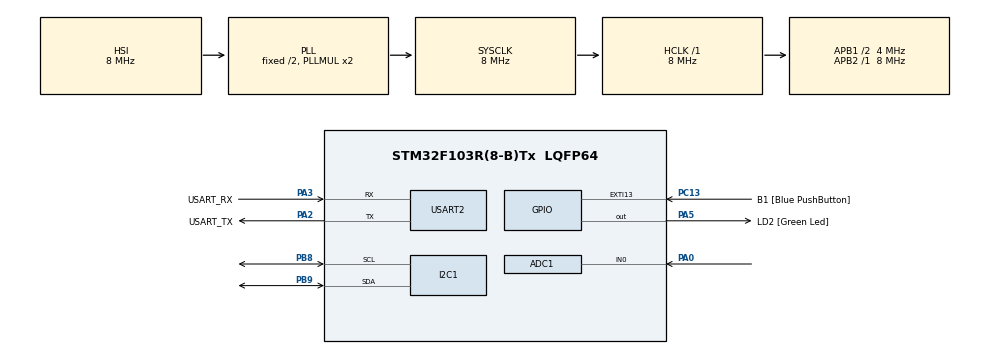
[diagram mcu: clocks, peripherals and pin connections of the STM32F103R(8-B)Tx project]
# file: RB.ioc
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ADC1.Channel-0\#ChannelRegularConversion=ADC_CHANNEL_0
ADC1.ContinuousConvMode=ENABLE
ADC1.NbrOfConversionFlag=1
ADC1.Rank-0\#ChannelRegularConversion=1
ADC1.SamplingTime-0\#ChannelRegularConversion=ADC_SAMPLETIME_1CYCLE_5
ADC1.master=1
Mcu.Family=STM32F1
Mcu.Name=STM32F103R(8-B)Tx
Mcu.Package=LQFP64
NVIC.ADC1_2_IRQn=true\:0\:0\:false\:false\:true\:true\:true\:true
NVIC.EXTI15_10_IRQn=true\:0\:0\:false\:false\:true\:true\:true\:true
NVIC.PriorityGroup=NVIC_PRIORITYGROUP_4
NVIC.TIM2_IRQn=true\:0\:0\:false\:false\:true\:true\:true\:true
PA0-WKUP.Signal=ADCx_IN0
PA13.GPIO_Label=TMS
PA13.Mode=Serial_Wire
PA13.Signal=SYS_JTMS-SWDIO
PA14.GPIO_Label=TCK
PA14.Mode=Serial_Wire
PA14.Signal=SYS_JTCK-SWCLK
PA2.GPIO_Label=USART_TX
PA2.GPIO_Mode=GPIO_MODE_AF_PP
PA2.GPIO_PuPd=GPIO_NOPULL
PA2.GPIO_Speed=GPIO_SPEED_FREQ_LOW
PA2.Mode=Asynchronous
PA2.Signal=USART2_TX
PA3.GPIO_Label=USART_RX
PA3.GPIO_Mode=GPIO_MODE_AF_PP
PA3.GPIO_PuPd=GPIO_NOPULL
PA3.GPIO_Speed=GPIO_SPEED_FREQ_LOW
PA3.Mode=Asynchronous
PA3.Signal=USART2_RX
PA5.GPIO_Label=LD2 [Green Led]
PA5.GPIO_ModeDefaultOutputPP=GPIO_MODE_OUTPUT_PP
PA5.GPIO_PuPd=GPIO_NOPULL
PA5.GPIO_Speed=GPIO_SPEED_FREQ_LOW
PA5.Signal=GPIO_Output
PB3.GPIO_Label=SWO
PB3.Signal=SYS_JTDO-TRACESWO
PB8.Mode=I2C
PB8.Signal=I2C1_SCL
PB9.Mode=I2C
PB9.Signal=I2C1_SDA
PC13-TAMPER-RTC.GPIO_Label=B1 [Blue PushButton]
PC13-TAMPER-RTC.GPIO_PuPd=GPIO_NOPULL
PC13-TAMPER-RTC.Signal=GPXTI13
PC14-OSC32_IN.Mode=LSE-External-Oscillator
PC14-OSC32_IN.Signal=RCC_OSC32_IN
PC15-OSC32_OUT.Mode=LSE-External-Oscillator
PC15-OSC32_OUT.Signal=RCC_OSC32_OUT
PD0-OSC_IN.Mode=HSE-External-Clock-Source
PD0-OSC_IN.Signal=RCC_OSC_IN
PD1-OSC_OUT.Mode=HSE-External-Clock-Source
PD1-OSC_OUT.Signal=RCC_OSC_OUT
ProjectManager.HeapSize=0x200
ProjectManager.StackSize=0x400
ProjectManager.TargetToolchain=STM32CubeIDE
RCC.AHBFreq_Value=8000000
RCC.APB1CLKDivider=RCC_HCLK_DIV2
RCC.APB1Freq_Value=4000000
RCC.APB1TimFreq_Value=8000000
RCC.APB2Freq_Value=8000000
RCC.APB2TimFreq_Value=8000000
RCC.HCLKFreq_Value=8000000
RCC.RTCClockSelection=RCC_RTCCLKSOURCE_LSE
RCC.SYSCLKFreq_VALUE=8000000
RCC.SYSCLKSource=RCC_SYSCLKSOURCE_PLLCLK
RCC.USBFreq_Value=8000000
SH.ADCx_IN0.0=ADC1_IN0,IN0
TIM2.Period=9
TIM2.Prescaler=63999
USART2.VirtualMode=VM_ASYNC
VP_TIM2_VS_ClockSourceINT.Mode=Internal
board=NUCLEO-F103RB

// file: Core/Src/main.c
/* USER CODE BEGIN Header */
/**
  ******************************************************************************
  * @file           : main.c
  * @brief          : Main program body
  ******************************************************************************
  * @attention
  *
  * Copyright (c) 2024 STMicroelectronics.
  * All rights reserved.
  *
  * This software is licensed under terms that can be found in the LICENSE file
  * in the root directory of this software component.
  * If no LICENSE file comes with this software, it is provided AS-IS.
  *
  ******************************************************************************
  */
/* USER CODE END Header */
#include "main.h"

/* USER CODE BEGIN Includes */
#include "i2c-lcd.h"
#include "input_processing.h"
#include "input_reading.h"
#include "scheduler.h"
#include "led_display.h"
/* USER CODE END Includes */

/* USER CODE BEGIN PD */
TIM_HandleTypeDef htim2;

/* USER CODE END PD */

ADC_HandleTypeDef hadc1;

I2C_HandleTypeDef hi2c1;

TIM_HandleTypeDef htim2;

UART_HandleTypeDef huart2;

void SystemClock_Config(void);
static void MX_GPIO_Init(void);
static void MX_USART2_UART_Init(void);
static void MX_I2C1_Init(void);
static void MX_ADC1_Init(void);
static void MX_TIM2_Init(void);
/* USER CODE BEGIN PFP */
ADC_HandleTypeDef hadc1;
/* USER CODE END PFP */

/* USER CODE BEGIN 0 */
void HAL_ADC_ConvCpltCallback(ADC_HandleTypeDef * hadc){

}
void HAL_TIM_PeriodElapsedCallback (TIM_HandleTypeDef *htim)
{
	  SCH_Update();  // Cập nhật scheduler mỗi 1ms

	}
/* USER CODE END 0 */

int main(void)
{

  /* MCU Configuration--------------------------------------------------------*/

  /* Reset of all peripherals, Initializes the Flash interface and the Systick. */
  HAL_Init();

  /* Configure the system clock */
  SystemClock_Config();

  /* Initialize all configured peripherals */
  MX_GPIO_Init();
  MX_USART2_UART_Init();
  MX_I2C1_Init();
  MX_ADC1_Init();
  MX_TIM2_Init();
  /* USER CODE BEGIN 2 */
  lcd_init();
  //lcd_clear();
  HAL_TIM_Base_Start_IT(&htim2);
  SCH_Init();
  //HAL_ADC_Start_IT(&hadc1);
  /* USER CODE END 2 */

  /* Infinite loop */
  /* USER CODE BEGIN WHILE */
  SCH_Add_Task(timeledlight, 0, 1);
  SCH_Add_Task(button_reading, 1, 1);
  SCH_Add_Task(handle_mode, 3, 10);
  SCH_Add_Task(fsm_for_input_processing, 4, 1);
//  SCH_Add_Task(timeledlight, 500, 500);
  while (1)
  {
	  SCH_Dispatch_Tasks();
	  lcd_goto_XY(1, 0);
	  //lcd_send_string("hehe");
    /* USER CODE END WHILE */

  }
}

void SystemClock_Config(void)
{
  RCC_OscInitTypeDef RCC_OscInitStruct = {0};
  RCC_ClkInitTypeDef RCC_ClkInitStruct = {0};
  RCC_PeriphCLKInitTypeDef PeriphClkInit = {0};

  /** Initializes the RCC Oscillators according to the specified parameters
  * in the RCC_OscInitTypeDef structure.
  */
  RCC_OscInitStruct.OscillatorType = RCC_OSCILLATORTYPE_HSI;
  RCC_OscInitStruct.HSIState = RCC_HSI_ON;
  RCC_OscInitStruct.HSICalibrationValue = RCC_HSICALIBRATION_DEFAULT;
  RCC_OscInitStruct.PLL.PLLState = RCC_PLL_ON;
  RCC_OscInitStruct.PLL.PLLSource = RCC_PLLSOURCE_HSI_DIV2;
  RCC_OscInitStruct.PLL.PLLMUL = RCC_PLL_MUL2;
  if (HAL_RCC_OscConfig(&RCC_OscInitStruct) != HAL_OK)
  {
    Error_Handler();
  }

  /** Initializes the CPU, AHB and APB buses clocks
  */
  RCC_ClkInitStruct.ClockType = RCC_CLOCKTYPE_HCLK|RCC_CLOCKTYPE_SYSCLK
                              |RCC_CLOCKTYPE_PCLK1|RCC_CLOCKTYPE_PCLK2;
  RCC_ClkInitStruct.SYSCLKSource = RCC_SYSCLKSOURCE_PLLCLK;
  RCC_ClkInitStruct.AHBCLKDivider = RCC_SYSCLK_DIV1;
  RCC_ClkInitStruct.APB1CLKDivider = RCC_HCLK_DIV2;
  RCC_ClkInitStruct.APB2CLKDivider = RCC_HCLK_DIV1;

  if (HAL_RCC_ClockConfig(&RCC_ClkInitStruct, FLASH_LATENCY_0) != HAL_OK)
  {
    Error_Handler();
  }
  PeriphClkInit.PeriphClockSelection = RCC_PERIPHCLK_ADC;
  PeriphClkInit.AdcClockSelection = RCC_ADCPCLK2_DIV2;
  if (HAL_RCCEx_PeriphCLKConfig(&PeriphClkInit) != HAL_OK)
  {
    Error_Handler();
  }
}

static void MX_ADC1_Init(void)
{

  ADC_ChannelConfTypeDef sConfig = {0};

  /** Common config
  */
  hadc1.Instance = ADC1;
  hadc1.Init.ScanConvMode = ADC_SCAN_DISABLE;
  hadc1.Init.ContinuousConvMode = ENABLE;
  hadc1.Init.DiscontinuousConvMode = DISABLE;
  hadc1.Init.ExternalTrigConv = ADC_SOFTWARE_START;
  hadc1.Init.DataAlign = ADC_DATAALIGN_RIGHT;
  hadc1.Init.NbrOfConversion = 1;
  if (HAL_ADC_Init(&hadc1) != HAL_OK)
  {
    Error_Handler();
  }

  /** Configure Regular Channel
  */
  sConfig.Channel = ADC_CHANNEL_0;
  sConfig.Rank = ADC_REGULAR_RANK_1;
  sConfig.SamplingTime = ADC_SAMPLETIME_1CYCLE_5;
  if (HAL_ADC_ConfigChannel(&hadc1, &sConfig) != HAL_OK)
  {
    Error_Handler();
  }

}

static void MX_I2C1_Init(void)
{

  hi2c1.Instance = I2C1;
  hi2c1.Init.ClockSpeed = 100000;
  hi2c1.Init.DutyCycle = I2C_DUTYCYCLE_2;
  hi2c1.Init.OwnAddress1 = 0;
  hi2c1.Init.AddressingMode = I2C_ADDRESSINGMODE_7BIT;
  hi2c1.Init.DualAddressMode = I2C_DUALADDRESS_DISABLE;
  hi2c1.Init.OwnAddress2 = 0;
  hi2c1.Init.GeneralCallMode = I2C_GENERALCALL_DISABLE;
  hi2c1.Init.NoStretchMode = I2C_NOSTRETCH_DISABLE;
  if (HAL_I2C_Init(&hi2c1) != HAL_OK)
  {
    Error_Handler();
  }

}

static void MX_TIM2_Init(void)
{

  TIM_ClockConfigTypeDef sClockSourceConfig = {0};
  TIM_MasterConfigTypeDef sMasterConfig = {0};

  htim2.Instance = TIM2;
  htim2.Init.Prescaler = 63999;
  htim2.Init.CounterMode = TIM_COUNTERMODE_UP;
  htim2.Init.Period = 9;
  htim2.Init.ClockDivision = TIM_CLOCKDIVISION_DIV1;
  htim2.Init.AutoReloadPreload = TIM_AUTORELOAD_PRELOAD_DISABLE;
  if (HAL_TIM_Base_Init(&htim2) != HAL_OK)
  {
    Error_Handler();
  }
  sClockSourceConfig.ClockSource = TIM_CLOCKSOURCE_INTERNAL;
  if (HAL_TIM_ConfigClockSource(&htim2, &sClockSourceConfig) != HAL_OK)
  {
    Error_Handler();
  }
  sMasterConfig.MasterOutputTrigger = TIM_TRGO_RESET;
  sMasterConfig.MasterSlaveMode = TIM_MASTERSLAVEMODE_DISABLE;
  if (HAL_TIMEx_MasterConfigSynchronization(&htim2, &sMasterConfig) != HAL_OK)
  {
    Error_Handler();
  }

}

static void MX_USART2_UART_Init(void)
{

  huart2.Instance = USART2;
  huart2.Init.BaudRate = 115200;
  huart2.Init.WordLength = UART_WORDLENGTH_8B;
  huart2.Init.StopBits = UART_STOPBITS_1;
  huart2.Init.Parity = UART_PARITY_NONE;
  huart2.Init.Mode = UART_MODE_TX_RX;
  huart2.Init.HwFlowCtl = UART_HWCONTROL_NONE;
  huart2.Init.OverSampling = UART_OVERSAMPLING_16;
  if (HAL_UART_Init(&huart2) != HAL_OK)
  {
    Error_Handler();
  }

}

static void MX_GPIO_Init(void)
{
  GPIO_InitTypeDef GPIO_InitStruct = {0};

  /* GPIO Ports Clock Enable */
  __HAL_RCC_GPIOC_CLK_ENABLE();
  __HAL_RCC_GPIOD_CLK_ENABLE();
  __HAL_RCC_GPIOA_CLK_ENABLE();
  __HAL_RCC_GPIOB_CLK_ENABLE();

  /*Configure GPIO pin Output Level */
  HAL_GPIO_WritePin(LD2_GPIO_Port, LD2_Pin, GPIO_PIN_RESET);

  /*Configure GPIO pin : B1_Pin */
  GPIO_InitStruct.Pin = B1_Pin;
  GPIO_InitStruct.Mode = GPIO_MODE_IT_RISING;
  GPIO_InitStruct.Pull = GPIO_NOPULL;
  HAL_GPIO_Init(B1_GPIO_Port, &GPIO_InitStruct);

  /*Configure GPIO pin : LD2_Pin */
  GPIO_InitStruct.Pin = LD2_Pin;
  GPIO_InitStruct.Mode = GPIO_MODE_OUTPUT_PP;
  GPIO_InitStruct.Pull = GPIO_NOPULL;
  GPIO_InitStruct.Speed = GPIO_SPEED_FREQ_LOW;
  HAL_GPIO_Init(LD2_GPIO_Port, &GPIO_InitStruct);
  /*Configure GPIO pin Output Level */
    HAL_GPIO_WritePin(GPIOB, red1_Pin|yellow1_Pin|green1_Pin|red2_Pin
                            |yellow2_Pin|green2_Pin|EN1_Pin|EN2_Pin
                            |EN3_Pin|EN4_Pin|mode_Pin|GPIO_PIN_6, GPIO_PIN_RESET);

    HAL_GPIO_WritePin(GPIOC, GPIO_PIN_7, GPIO_PIN_RESET);

    /* Configure GPIO pins for GPIOC: PC7 */
    GPIO_InitStruct.Pin = GPIO_PIN_7;
    GPIO_InitStruct.Mode = GPIO_MODE_OUTPUT_PP;
    GPIO_InitStruct.Pull = GPIO_NOPULL;
    GPIO_InitStruct.Speed = GPIO_SPEED_FREQ_LOW;
    HAL_GPIO_Init(GPIOC, &GPIO_InitStruct);

    /* Configure GPIO pins for GPIOB: PB6 */
    GPIO_InitStruct.Pin = GPIO_PIN_6;
    HAL_GPIO_Init(GPIOB, &GPIO_InitStruct);

    /* Configure other GPIO pins as needed */
    GPIO_InitStruct.Pin = red1_Pin|yellow1_Pin|green1_Pin|red2_Pin
                            |yellow2_Pin|green2_Pin|EN1_Pin|EN2_Pin
                            |EN3_Pin|EN4_Pin|mode_Pin;
    HAL_GPIO_Init(GPIOB, &GPIO_InitStruct);

    /* Configure input pins for buttons */
    GPIO_InitStruct.Pin = BUTTON_1_Pin|BUTTON_2_Pin;
    GPIO_InitStruct.Mode = GPIO_MODE_INPUT;
    GPIO_InitStruct.Pull = GPIO_PULLUP;
    HAL_GPIO_Init(GPIOB, &GPIO_InitStruct);

    GPIO_InitStruct.Pin = BUTTON_3_Pin|BUTTON_4_Pin;
      GPIO_InitStruct.Mode = GPIO_MODE_INPUT;
      GPIO_InitStruct.Pull = GPIO_PULLUP;
      HAL_GPIO_Init(GPIOA, &GPIO_InitStruct);
  /* EXTI interrupt init*/
  HAL_NVIC_SetPriority(EXTI15_10_IRQn, 0, 0);
  HAL_NVIC_EnableIRQ(EXTI15_10_IRQn);

}

void Error_Handler(void)
{
  __disable_irq();
  while (1)
  {
  }
}
